VERSION 5.7 ;
  NOWIREEXTENSIONATPIN ON ;
  DIVIDERCHAR "/" ;
  BUSBITCHARS "[]" ;
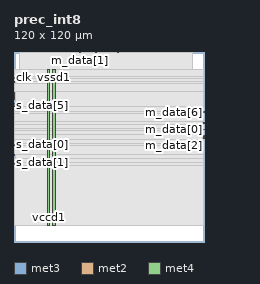
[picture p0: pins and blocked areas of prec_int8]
MACRO prec_int8
  CLASS BLOCK ;
  FOREIGN prec_int8 ;
  ORIGIN 0.000 0.000 ;
  SIZE 120.000 BY 120.000 ;
  PIN clk
    DIRECTION INPUT ;
    USE SIGNAL ;
    ANTENNAGATEAREA 1.286700 ;
    ANTENNADIFFAREA 0.434700 ;
    PORT
      LAYER met3 ;
        RECT 0.000 103.400 0.600 104.000 ;
    END
  END clk
  PIN m_data[0]
    DIRECTION OUTPUT ;
    USE SIGNAL ;
    ANTENNADIFFAREA 0.795200 ;
    PORT
      LAYER met3 ;
        RECT 119.400 70.760 120.000 71.360 ;
    END
  END m_data[0]
  PIN m_data[1]
    DIRECTION OUTPUT ;
    USE SIGNAL ;
    ANTENNADIFFAREA 0.795200 ;
    PORT
      LAYER met2 ;
        RECT 41.490 119.720 41.770 120.000 ;
    END
  END m_data[1]
  PIN m_data[2]
    DIRECTION OUTPUT ;
    USE SIGNAL ;
    ANTENNADIFFAREA 0.795200 ;
    PORT
      LAYER met3 ;
        RECT 119.400 65.320 120.000 65.920 ;
    END
  END m_data[2]
  PIN m_data[3]
    DIRECTION OUTPUT ;
    USE SIGNAL ;
    ANTENNADIFFAREA 0.795200 ;
    PORT
      LAYER met2 ;
        RECT 51.610 119.720 51.890 120.000 ;
    END
  END m_data[3]
  PIN m_data[4]
    DIRECTION OUTPUT ;
    USE SIGNAL ;
    ANTENNADIFFAREA 0.795200 ;
    PORT
      LAYER met2 ;
        RECT 65.410 119.720 65.690 120.000 ;
    END
  END m_data[4]
  PIN m_data[5]
    DIRECTION OUTPUT ;
    USE SIGNAL ;
    ANTENNADIFFAREA 0.795200 ;
    PORT
      LAYER met2 ;
        RECT 77.370 119.720 77.650 120.000 ;
    END
  END m_data[5]
  PIN m_data[6]
    DIRECTION OUTPUT ;
    USE SIGNAL ;
    ANTENNADIFFAREA 0.795200 ;
    PORT
      LAYER met3 ;
        RECT 119.400 81.640 120.000 82.240 ;
    END
  END m_data[6]
  PIN m_data[7]
    DIRECTION OUTPUT ;
    USE SIGNAL ;
    ANTENNADIFFAREA 0.795200 ;
    PORT
      LAYER met3 ;
        RECT 119.400 74.840 120.000 75.440 ;
    END
  END m_data[7]
  PIN m_last
    DIRECTION OUTPUT ;
    USE SIGNAL ;
    ANTENNADIFFAREA 0.795200 ;
    PORT
      LAYER met3 ;
        RECT 119.400 66.680 120.000 67.280 ;
    END
  END m_last
  PIN m_ready
    DIRECTION INPUT ;
    USE SIGNAL ;
    ANTENNAGATEAREA 0.647700 ;
    ANTENNADIFFAREA 0.434700 ;
    PORT
      LAYER met2 ;
        RECT 35.050 119.720 35.330 120.000 ;
    END
  END m_ready
  PIN m_valid
    DIRECTION OUTPUT ;
    USE SIGNAL ;
    ANTENNADIFFAREA 0.795200 ;
    PORT
      LAYER met2 ;
        RECT 36.890 119.720 37.170 120.000 ;
    END
  END m_valid
  PIN rst
    DIRECTION INPUT ;
    USE SIGNAL ;
    ANTENNAGATEAREA 0.631200 ;
    ANTENNADIFFAREA 0.434700 ;
    PORT
      LAYER met3 ;
        RECT 0.000 100.680 0.600 101.280 ;
    END
  END rst
  PIN s_data[0]
    DIRECTION INPUT ;
    USE SIGNAL ;
    ANTENNAGATEAREA 0.647700 ;
    ANTENNADIFFAREA 0.434700 ;
    PORT
      LAYER met3 ;
        RECT 0.000 61.240 0.600 61.840 ;
    END
  END s_data[0]
  PIN s_data[1]
    DIRECTION INPUT ;
    USE SIGNAL ;
    ANTENNAGATEAREA 0.647700 ;
    ANTENNADIFFAREA 0.434700 ;
    PORT
      LAYER met3 ;
        RECT 0.000 54.440 0.600 55.040 ;
    END
  END s_data[1]
  PIN s_data[2]
    DIRECTION INPUT ;
    USE SIGNAL ;
    ANTENNAGATEAREA 0.647700 ;
    ANTENNADIFFAREA 0.434700 ;
    PORT
      LAYER met3 ;
        RECT 0.000 53.080 0.600 53.680 ;
    END
  END s_data[2]
  PIN s_data[3]
    DIRECTION INPUT ;
    USE SIGNAL ;
    ANTENNAGATEAREA 0.647700 ;
    ANTENNADIFFAREA 0.434700 ;
    PORT
      LAYER met3 ;
        RECT 0.000 49.000 0.600 49.600 ;
    END
  END s_data[3]
  PIN s_data[4]
    DIRECTION INPUT ;
    USE SIGNAL ;
    ANTENNAGATEAREA 0.647700 ;
    ANTENNADIFFAREA 0.434700 ;
    PORT
      LAYER met3 ;
        RECT 0.000 89.800 0.600 90.400 ;
    END
  END s_data[4]
  PIN s_data[5]
    DIRECTION INPUT ;
    USE SIGNAL ;
    ANTENNAGATEAREA 0.647700 ;
    ANTENNADIFFAREA 0.434700 ;
    PORT
      LAYER met3 ;
        RECT 0.000 85.720 0.600 86.320 ;
    END
  END s_data[5]
  PIN s_data[6]
    DIRECTION INPUT ;
    USE SIGNAL ;
    ANTENNAGATEAREA 0.647700 ;
    ANTENNADIFFAREA 0.434700 ;
    PORT
      LAYER met3 ;
        RECT 0.000 87.080 0.600 87.680 ;
    END
  END s_data[6]
  PIN s_data[7]
    DIRECTION INPUT ;
    USE SIGNAL ;
    ANTENNAGATEAREA 0.647700 ;
    ANTENNADIFFAREA 0.434700 ;
    PORT
      LAYER met3 ;
        RECT 0.000 88.440 0.600 89.040 ;
    END
  END s_data[7]
  PIN s_last
    DIRECTION INPUT ;
    USE SIGNAL ;
    ANTENNAGATEAREA 0.647700 ;
    ANTENNADIFFAREA 0.434700 ;
    PORT
      LAYER met3 ;
        RECT 0.000 93.880 0.600 94.480 ;
    END
  END s_last
  PIN s_ready
    DIRECTION OUTPUT ;
    USE SIGNAL ;
    ANTENNADIFFAREA 0.795200 ;
    PORT
      LAYER met3 ;
        RECT 0.000 92.520 0.600 93.120 ;
    END
  END s_ready
  PIN s_valid
    DIRECTION INPUT ;
    USE SIGNAL ;
    ANTENNAGATEAREA 0.647700 ;
    ANTENNADIFFAREA 0.434700 ;
    PORT
      LAYER met3 ;
        RECT 0.000 91.160 0.600 91.760 ;
    END
  END s_valid
  PIN vccd1
    DIRECTION INOUT ;
    USE POWER ;
    PORT
      LAYER met4 ;
        RECT 21.040 10.640 22.640 109.040 ;
    END
  END vccd1
  PIN vssd1
    DIRECTION INOUT ;
    USE GROUND ;
    PORT
      LAYER met4 ;
        RECT 24.340 10.640 25.940 109.040 ;
    END
  END vssd1
  OBS
      LAYER nwell ;
        RECT 5.330 10.795 114.270 108.885 ;
      LAYER li1 ;
        RECT 5.520 10.795 114.080 108.885 ;
      LAYER met1 ;
        RECT 3.750 10.640 114.380 109.040 ;
      LAYER met2 ;
        RECT 3.770 119.440 34.770 119.720 ;
        RECT 35.610 119.440 36.610 119.720 ;
        RECT 37.450 119.440 41.210 119.720 ;
        RECT 42.050 119.440 51.330 119.720 ;
        RECT 52.170 119.440 65.130 119.720 ;
        RECT 65.970 119.440 77.090 119.720 ;
        RECT 77.930 119.440 112.600 119.720 ;
        RECT 3.770 10.695 112.600 119.440 ;
      LAYER met3 ;
        RECT 0.600 104.400 119.400 108.965 ;
        RECT 1.000 103.000 119.400 104.400 ;
        RECT 0.600 101.680 119.400 103.000 ;
        RECT 1.000 100.280 119.400 101.680 ;
        RECT 0.600 94.880 119.400 100.280 ;
        RECT 1.000 85.320 119.400 94.880 ;
        RECT 0.600 82.640 119.400 85.320 ;
        RECT 0.600 81.240 119.000 82.640 ;
        RECT 0.600 75.840 119.400 81.240 ;
        RECT 0.600 74.440 119.000 75.840 ;
        RECT 0.600 71.760 119.400 74.440 ;
        RECT 0.600 70.360 119.000 71.760 ;
        RECT 0.600 67.680 119.400 70.360 ;
        RECT 0.600 64.920 119.000 67.680 ;
        RECT 0.600 62.240 119.400 64.920 ;
        RECT 1.000 60.840 119.400 62.240 ;
        RECT 0.600 55.440 119.400 60.840 ;
        RECT 1.000 52.680 119.400 55.440 ;
        RECT 0.600 50.000 119.400 52.680 ;
        RECT 1.000 48.600 119.400 50.000 ;
        RECT 0.600 10.715 119.400 48.600 ;
  END
END prec_int8
END LIBRARY

